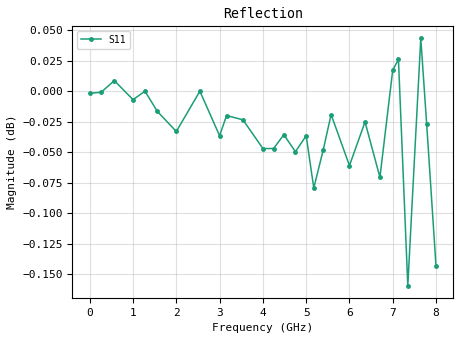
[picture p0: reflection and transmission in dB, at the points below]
!  22/10/2019  12:27:12
! Ref Plane: 0.000 mm
# MHZ S MA R  50
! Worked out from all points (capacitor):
!   2001 points, 300 kHz to 8 GHz, reference 50 ohm
!   read as one part to ground: C = 972 fF near 40.3 MHz
!   lowest |Z| = 232 mohm at 5.176 GHz (marker M1)
!   series resonance near 5.174 GHz, so ESL is about 970 pH
!   S11 on the Smith chart (normalised r, x): 300 kHz: open; 1.56 GHz: 0.00, -1.91; 3.16 GHz: 0.00, -0.70; 4.752 GHz: 0.00, -0.13; 6.36 GHz: 0.00, +0.37; 8 GHz: 0.02, +1.10
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0.3  0.9998 -0.0
264.2934  0.9999 -9.3
568.2858  1.001 -20.2
1000.275  0.9992 -35.4
1276.268  1 -44.9
1560.261  0.9981 -55.1
2000.25  0.9962 -70.4
2544.236  1 -89.0
3000.225  0.9958 -105.0
3160.221  0.9977 -110.3
3540.211  0.9973 -123.2
4000.2  0.9946 -139.5
4248.194  0.9946 -147.5
4484.188  0.9959 -156.4
4752.181  0.9943 -165.5
5000.175  0.9958 -173.5
5176.171  0.9909 179.9
5396.165  0.9945 170.2
5576.161  0.9978 166.2
6000.15  0.993 150.3
6360.141  0.9971 139.3
6704.132  0.9919 126.7
7000.125  1.002 117.2
7132.122  1.003 113.4
7348.116  0.9818 104.5
7648.109  1.005 95.9
7784.105  0.9969 92.5
8000.1  0.9836 84.3
